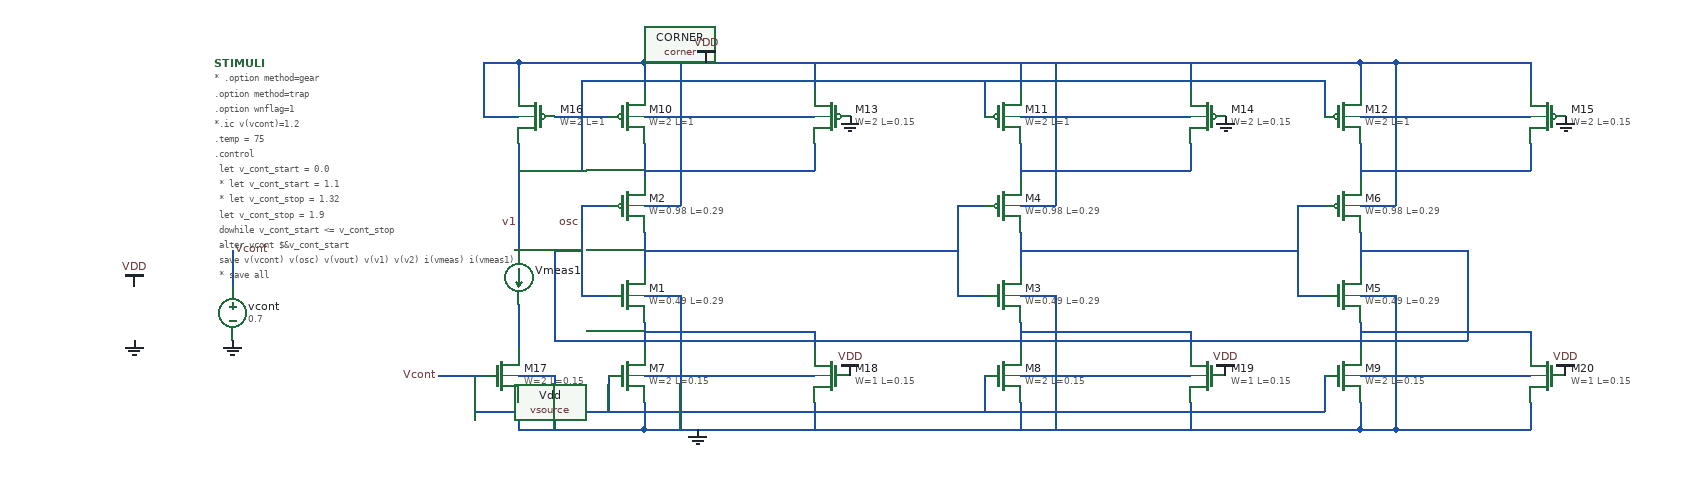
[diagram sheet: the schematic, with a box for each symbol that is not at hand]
v {xschem version=3.4.5 file_version=1.2
}
G {}
K {}
V {}
S {}
E {}
B 2 20 -1720 1940 -940 {flags=graph
y1=-0.052
y2=1.9
ypos1=0
ypos2=2
divy=5
subdivy=1
unity=1
x1=2.1401577e-08
x2=2.3050844e-08
divx=5
subdivx=4
xlabmag=1.0
ylabmag=1.0


dataset=-1
unitx=1
logx=0
logy=0
linewidth_mult=3




color=5
node=osc}
N 350 -670 350 -630 {
lab=Vcont}
N 810 -690 810 -650 {
lab=#net1}
N 740 -720 770 -720 {
lab=osc}
N 740 -720 740 -620 {
lab=osc}
N 740 -620 770 -620 {
lab=osc}
N 1230 -690 1230 -650 {
lab=#net2}
N 1160 -720 1190 -720 {
lab=#net1}
N 1160 -720 1160 -620 {
lab=#net1}
N 1160 -620 1190 -620 {
lab=#net1}
N 810 -670 1160 -670 {
lab=#net1}
N 1610 -690 1610 -650 {
lab=osc}
N 1540 -720 1570 -720 {
lab=#net2}
N 1540 -720 1540 -620 {
lab=#net2}
N 1540 -620 1570 -620 {
lab=#net2}
N 1230 -670 1540 -670 {
lab=#net2}
N 810 -500 810 -470 {
lab=GND}
N 810 -470 1610 -470 {
lab=GND}
N 1610 -500 1610 -470 {
lab=GND}
N 1230 -500 1230 -470 {
lab=GND}
N 1610 -670 1730 -670 {
lab=osc}
N 1730 -670 1730 -570 {
lab=osc}
N 710 -570 1730 -570 {
lab=osc}
N 710 -670 710 -570 {
lab=osc}
N 710 -670 740 -670 {
lab=osc}
N 810 -790 810 -750 {
lab=#net3}
N 810 -790 810 -750 {
lab=#net3}
N 1230 -790 1230 -750 {
lab=#net4}
N 1610 -790 1610 -750 {
lab=#net5}
N 810 -880 810 -850 {
lab=VDD}
N 810 -880 1610 -880 {
lab=VDD}
N 1610 -880 1610 -850 {
lab=VDD}
N 1230 -880 1230 -850 {
lab=VDD}
N 670 -880 670 -850 {
lab=VDD}
N 670 -880 810 -880 {
lab=VDD}
N 740 -820 740 -760 {
lab=v1}
N 670 -760 740 -760 {
lab=v1}
N 670 -500 670 -470 {
lab=GND}
N 670 -470 810 -470 {
lab=GND}
N 580 -530 630 -530 {
lab=Vcont}
N 1610 -590 1610 -560 {
lab=#net6}
N 1230 -590 1230 -560 {
lab=#net7}
N 810 -590 810 -560 {
lab=#net8}
N 810 -720 850 -720 {
lab=VDD}
N 850 -880 850 -720 {
lab=VDD}
N 850 -620 850 -470 {
lab=GND}
N 810 -530 850 -530 {
lab=GND}
N 1230 -620 1270 -620 {
lab=GND}
N 1270 -620 1270 -470 {
lab=GND}
N 1230 -530 1270 -530 {
lab=GND}
N 1610 -620 1650 -620 {
lab=GND}
N 1650 -620 1650 -470 {
lab=GND}
N 1610 -470 1650 -470 {
lab=GND}
N 1610 -530 1650 -530 {
lab=GND}
N 710 -820 770 -820 {
lab=v1}
N 810 -820 850 -820 {
lab=VDD}
N 1230 -820 1270 -820 {
lab=VDD}
N 1230 -720 1270 -720 {
lab=VDD}
N 1270 -880 1270 -720 {
lab=VDD}
N 1610 -820 1650 -820 {
lab=VDD}
N 1610 -880 1650 -880 {
lab=VDD}
N 1650 -880 1650 -720 {
lab=VDD}
N 1610 -720 1650 -720 {
lab=VDD}
N 740 -860 740 -820 {
lab=v1}
N 740 -860 1570 -860 {
lab=v1}
N 1570 -860 1570 -820 {
lab=v1}
N 1190 -860 1190 -820 {
lab=v1}
N 620 -530 620 -490 {
lab=Vcont}
N 620 -490 1570 -490 {
lab=Vcont}
N 1570 -530 1570 -490 {
lab=Vcont}
N 1190 -530 1190 -490 {
lab=Vcont}
N 770 -530 770 -490 {
lab=Vcont}
N 630 -820 670 -820 {
lab=VDD}
N 630 -880 630 -820 {
lab=VDD}
N 630 -880 670 -880 {
lab=VDD}
N 670 -530 710 -530 {
lab=GND}
N 710 -530 710 -470 {
lab=GND}
N 670 -610 670 -560 {
lab=#net9}
N 670 -790 670 -670 {
lab=v1}
N 1000 -880 1000 -850 {
lab=VDD}
N 850 -820 1000 -820 {
lab=VDD}
N 1000 -790 1000 -760 {
lab=#net3}
N 810 -760 1000 -760 {
lab=#net3}
N 1420 -880 1420 -850 {
lab=VDD}
N 1270 -820 1420 -820 {
lab=VDD}
N 1230 -760 1420 -760 {
lab=#net4}
N 1420 -790 1420 -760 {
lab=#net4}
N 1800 -880 1800 -850 {
lab=VDD}
N 1650 -820 1800 -820 {
lab=VDD}
N 1610 -760 1800 -760 {
lab=#net5}
N 1800 -790 1800 -760 {
lab=#net5}
N 1650 -880 1800 -880 {
lab=VDD}
N 810 -580 1000 -580 {
lab=#net8}
N 1000 -580 1000 -550 {
lab=#net8}
N 850 -530 1000 -530 {
lab=GND}
N 1000 -500 1000 -470 {
lab=GND}
N 1230 -580 1420 -580 {
lab=#net7}
N 1420 -580 1420 -550 {
lab=#net7}
N 1270 -530 1420 -530 {
lab=GND}
N 1420 -500 1420 -470 {
lab=GND}
N 1610 -580 1800 -580 {
lab=#net6}
N 1800 -580 1800 -550 {
lab=#net6}
N 1650 -530 1800 -530 {
lab=GND}
N 1800 -500 1800 -470 {
lab=GND}
N 1650 -470 1800 -470 {
lab=GND}
N 810 -620 850 -620 {
lab=GND}
C {devices/vsource.sym} 240 -600 0 0 {name=Vdd value=1.8 savecurrent=false
* "pwl()"}
C {devices/gnd.sym} 240 -570 0 0 {name=l3 lab=GND}
C {devices/vdd.sym} 240 -630 0 0 {name=l4 lab=VDD}
C {devices/vsource.sym} 350 -600 0 0 {name=vcont value=0.7 savecurrent=false}
C {devices/gnd.sym} 350 -570 0 0 {name=l5 lab=GND}
C {devices/lab_pin.sym} 350 -670 0 1 {name=p1 sig_type=std_logic lab=Vcont}
C {sky130_fd_pr/corner.sym} 180 -880 0 0 {name=CORNER only_toplevel=false corner=tt}
C {devices/code.sym} 330 -878.75 0 0 {name=STIMULI only_toplevel=false value="

* .option method=gear
.option method=trap
.option wnflag=1


*.ic v(vcont)=1.2

.temp = 75

.control

  let v_cont_start = 0.0
  * let v_cont_start = 1.1
  * let v_cont_stop = 1.32
  let v_cont_stop = 1.9  

  dowhile v_cont_start <= v_cont_stop
    alter vcont $&v_cont_start
    save v(vcont) v(osc) v(vout) v(v1) v(v2) i(vmeas) i(vmeas1)
    * save all
    tran 1ps 30ns
    remzerovec
    write tb_current_starved_VCO4_4_\{$&v_cont_start\}.raw
    * write tb_current_starved_VCO4_4_.raw
    linearize v(osc)
    let filename = v_cont_start * 100
    wrdata /foss/designs/my_design/projects/pll/vco/xschem_ngspice/tb_current_starved_VCO4_4_\{$&filename\}.txt v(osc)
    set appendwrite

    reset
    let v_cont_start = v_cont_start + 0.1
  end
.endc


"}
C {devices/vdd.sym} 880 -880 0 0 {name=l1 lab=VDD}
C {devices/gnd.sym} 870 -470 0 0 {name=l2 lab=GND}
C {sky130_fd_pr/nfet_01v8.sym} 790 -620 0 0 {name=M1
L=0.29
W=0.49
nf=1 
mult=1
ad="'int((nf+1)/2) * W/nf * 0.29'" 
pd="'2*int((nf+1)/2) * (W/nf + 0.29)'"
as="'int((nf+2)/2) * W/nf * 0.29'" 
ps="'2*int((nf+2)/2) * (W/nf + 0.29)'"
nrd="'0.29 / W'" nrs="'0.29 / W'"
sa=0 sb=0 sd=0
model=nfet_01v8
spiceprefix=X
}
C {sky130_fd_pr/pfet_01v8.sym} 790 -720 0 0 {name=M2
L=0.29
W=0.98
nf=2
mult=1
ad="'int((nf+1)/2) * W/nf * 0.29'" 
pd="'2*int((nf+1)/2) * (W/nf + 0.29)'"
as="'int((nf+2)/2) * W/nf * 0.29'" 
ps="'2*int((nf+2)/2) * (W/nf + 0.29)'"
nrd="'0.29 / W'" nrs="'0.29 / W'"
sa=0 sb=0 sd=0
model=pfet_01v8
spiceprefix=X
}
C {sky130_fd_pr/nfet_01v8.sym} 1210 -620 0 0 {name=M3
L=0.29
W=0.49
nf=1 
mult=1
ad="'int((nf+1)/2) * W/nf * 0.29'" 
pd="'2*int((nf+1)/2) * (W/nf + 0.29)'"
as="'int((nf+2)/2) * W/nf * 0.29'" 
ps="'2*int((nf+2)/2) * (W/nf + 0.29)'"
nrd="'0.29 / W'" nrs="'0.29 / W'"
sa=0 sb=0 sd=0
model=nfet_01v8
spiceprefix=X
}
C {sky130_fd_pr/pfet_01v8.sym} 1210 -720 0 0 {name=M4
L=0.29
W=0.98
nf=2
mult=1
ad="'int((nf+1)/2) * W/nf * 0.29'" 
pd="'2*int((nf+1)/2) * (W/nf + 0.29)'"
as="'int((nf+2)/2) * W/nf * 0.29'" 
ps="'2*int((nf+2)/2) * (W/nf + 0.29)'"
nrd="'0.29 / W'" nrs="'0.29 / W'"
sa=0 sb=0 sd=0
model=pfet_01v8
spiceprefix=X
}
C {sky130_fd_pr/nfet_01v8.sym} 1590 -620 0 0 {name=M5
L=0.29
W=0.49
nf=1 
mult=1
ad="'int((nf+1)/2) * W/nf * 0.29'" 
pd="'2*int((nf+1)/2) * (W/nf + 0.29)'"
as="'int((nf+2)/2) * W/nf * 0.29'" 
ps="'2*int((nf+2)/2) * (W/nf + 0.29)'"
nrd="'0.29 / W'" nrs="'0.29 / W'"
sa=0 sb=0 sd=0
model=nfet_01v8
spiceprefix=X
}
C {sky130_fd_pr/pfet_01v8.sym} 1590 -720 0 0 {name=M6
L=0.29
W=0.98
nf=2
mult=1
ad="'int((nf+1)/2) * W/nf * 0.29'" 
pd="'2*int((nf+1)/2) * (W/nf + 0.29)'"
as="'int((nf+2)/2) * W/nf * 0.29'" 
ps="'2*int((nf+2)/2) * (W/nf + 0.29)'"
nrd="'0.29 / W'" nrs="'0.29 / W'"
sa=0 sb=0 sd=0
model=pfet_01v8
spiceprefix=X
}
C {sky130_fd_pr/nfet_01v8.sym} 790 -530 0 0 {name=M7
L=0.15
W=2
nf=1 
mult=1
ad="'int((nf+1)/2) * W/nf * 0.29'" 
pd="'2*int((nf+1)/2) * (W/nf + 0.29)'"
as="'int((nf+2)/2) * W/nf * 0.29'" 
ps="'2*int((nf+2)/2) * (W/nf + 0.29)'"
nrd="'0.29 / W'" nrs="'0.29 / W'"
sa=0 sb=0 sd=0
model=nfet_01v8
spiceprefix=X
}
C {sky130_fd_pr/nfet_01v8.sym} 1210 -530 0 0 {name=M8
L=0.15
W=2
nf=1 
mult=1
ad="'int((nf+1)/2) * W/nf * 0.29'" 
pd="'2*int((nf+1)/2) * (W/nf + 0.29)'"
as="'int((nf+2)/2) * W/nf * 0.29'" 
ps="'2*int((nf+2)/2) * (W/nf + 0.29)'"
nrd="'0.29 / W'" nrs="'0.29 / W'"
sa=0 sb=0 sd=0
model=nfet_01v8
spiceprefix=X
}
C {sky130_fd_pr/nfet_01v8.sym} 1590 -530 0 0 {name=M9
L=0.15
W=2
nf=1 
mult=1
ad="'int((nf+1)/2) * W/nf * 0.29'" 
pd="'2*int((nf+1)/2) * (W/nf + 0.29)'"
as="'int((nf+2)/2) * W/nf * 0.29'" 
ps="'2*int((nf+2)/2) * (W/nf + 0.29)'"
nrd="'0.29 / W'" nrs="'0.29 / W'"
sa=0 sb=0 sd=0
model=nfet_01v8
spiceprefix=X
}
C {sky130_fd_pr/pfet_01v8.sym} 790 -820 0 0 {name=M10
L=1
W=2
nf=1
mult=1
ad="'int((nf+1)/2) * W/nf * 0.29'" 
pd="'2*int((nf+1)/2) * (W/nf + 0.29)'"
as="'int((nf+2)/2) * W/nf * 0.29'" 
ps="'2*int((nf+2)/2) * (W/nf + 0.29)'"
nrd="'0.29 / W'" nrs="'0.29 / W'"
sa=0 sb=0 sd=0
model=pfet_01v8
spiceprefix=X
}
C {sky130_fd_pr/pfet_01v8.sym} 1210 -820 0 0 {name=M11
L=1
W=2
nf=1
mult=1
ad="'int((nf+1)/2) * W/nf * 0.29'" 
pd="'2*int((nf+1)/2) * (W/nf + 0.29)'"
as="'int((nf+2)/2) * W/nf * 0.29'" 
ps="'2*int((nf+2)/2) * (W/nf + 0.29)'"
nrd="'0.29 / W'" nrs="'0.29 / W'"
sa=0 sb=0 sd=0
model=pfet_01v8
spiceprefix=X
}
C {sky130_fd_pr/pfet_01v8.sym} 1590 -820 0 0 {name=M12
L=1
W=2
nf=1
mult=1
ad="'int((nf+1)/2) * W/nf * 0.29'" 
pd="'2*int((nf+1)/2) * (W/nf + 0.29)'"
as="'int((nf+2)/2) * W/nf * 0.29'" 
ps="'2*int((nf+2)/2) * (W/nf + 0.29)'"
nrd="'0.29 / W'" nrs="'0.29 / W'"
sa=0 sb=0 sd=0
model=pfet_01v8
spiceprefix=X
}
C {sky130_fd_pr/pfet_01v8.sym} 690 -820 0 1 {name=M16
L=1
W=2
nf=1
mult=1
ad="'int((nf+1)/2) * W/nf * 0.29'" 
pd="'2*int((nf+1)/2) * (W/nf + 0.29)'"
as="'int((nf+2)/2) * W/nf * 0.29'" 
ps="'2*int((nf+2)/2) * (W/nf + 0.29)'"
nrd="'0.29 / W'" nrs="'0.29 / W'"
sa=0 sb=0 sd=0
model=pfet_01v8
spiceprefix=X
}
C {sky130_fd_pr/nfet_01v8.sym} 650 -530 0 0 {name=M17
L=0.15
W=2
nf=1 
mult=1
ad="'int((nf+1)/2) * W/nf * 0.29'" 
pd="'2*int((nf+1)/2) * (W/nf + 0.29)'"
as="'int((nf+2)/2) * W/nf * 0.29'" 
ps="'2*int((nf+2)/2) * (W/nf + 0.29)'"
nrd="'0.29 / W'" nrs="'0.29 / W'"
sa=0 sb=0 sd=0
model=nfet_01v8
spiceprefix=X
}
C {devices/lab_pin.sym} 580 -530 0 0 {name=p2 sig_type=std_logic lab=Vcont}
C {devices/lab_pin.sym} 740 -700 0 0 {name=p3 sig_type=std_logic lab=osc}
C {devices/lab_pin.sym} 670 -700 0 0 {name=p4 sig_type=std_logic lab=v1}
C {devices/ammeter.sym} 670 -640 0 0 {name=Vmeas1 savecurrent=true spice_ignore=0}
C {sky130_fd_pr/pfet_01v8.sym} 1020 -820 0 1 {name=M13
L=0.15
W=2
nf=2
mult=1
ad="'int((nf+1)/2) * W/nf * 0.29'" 
pd="'2*int((nf+1)/2) * (W/nf + 0.29)'"
as="'int((nf+2)/2) * W/nf * 0.29'" 
ps="'2*int((nf+2)/2) * (W/nf + 0.29)'"
nrd="'0.29 / W'" nrs="'0.29 / W'"
sa=0 sb=0 sd=0
model=pfet_01v8
spiceprefix=X
}
C {devices/gnd.sym} 1040 -820 0 0 {name=l6 lab=GND}
C {sky130_fd_pr/pfet_01v8.sym} 1440 -820 0 1 {name=M14
L=0.15
W=2
nf=2
mult=1
ad="'int((nf+1)/2) * W/nf * 0.29'" 
pd="'2*int((nf+1)/2) * (W/nf + 0.29)'"
as="'int((nf+2)/2) * W/nf * 0.29'" 
ps="'2*int((nf+2)/2) * (W/nf + 0.29)'"
nrd="'0.29 / W'" nrs="'0.29 / W'"
sa=0 sb=0 sd=0
model=pfet_01v8
spiceprefix=X
}
C {devices/gnd.sym} 1460 -820 0 0 {name=l7 lab=GND}
C {sky130_fd_pr/pfet_01v8.sym} 1820 -820 0 1 {name=M15
L=0.15
W=2
nf=2
mult=1
ad="'int((nf+1)/2) * W/nf * 0.29'" 
pd="'2*int((nf+1)/2) * (W/nf + 0.29)'"
as="'int((nf+2)/2) * W/nf * 0.29'" 
ps="'2*int((nf+2)/2) * (W/nf + 0.29)'"
nrd="'0.29 / W'" nrs="'0.29 / W'"
sa=0 sb=0 sd=0
model=pfet_01v8
spiceprefix=X
}
C {devices/gnd.sym} 1840 -820 0 0 {name=l8 lab=GND}
C {sky130_fd_pr/nfet_01v8.sym} 1020 -530 0 1 {name=M18
L=0.15
W=1
nf=1 
mult=1
ad="'int((nf+1)/2) * W/nf * 0.29'" 
pd="'2*int((nf+1)/2) * (W/nf + 0.29)'"
as="'int((nf+2)/2) * W/nf * 0.29'" 
ps="'2*int((nf+2)/2) * (W/nf + 0.29)'"
nrd="'0.29 / W'" nrs="'0.29 / W'"
sa=0 sb=0 sd=0
model=nfet_01v8
spiceprefix=X
}
C {devices/vdd.sym} 1040 -530 0 0 {name=l9 lab=VDD}
C {sky130_fd_pr/nfet_01v8.sym} 1440 -530 0 1 {name=M19
L=0.15
W=1
nf=1 
mult=1
ad="'int((nf+1)/2) * W/nf * 0.29'" 
pd="'2*int((nf+1)/2) * (W/nf + 0.29)'"
as="'int((nf+2)/2) * W/nf * 0.29'" 
ps="'2*int((nf+2)/2) * (W/nf + 0.29)'"
nrd="'0.29 / W'" nrs="'0.29 / W'"
sa=0 sb=0 sd=0
model=nfet_01v8
spiceprefix=X
}
C {devices/vdd.sym} 1460 -530 0 0 {name=l10 lab=VDD}
C {sky130_fd_pr/nfet_01v8.sym} 1820 -530 0 1 {name=M20
L=0.15
W=1
nf=1 
mult=1
ad="'int((nf+1)/2) * W/nf * 0.29'" 
pd="'2*int((nf+1)/2) * (W/nf + 0.29)'"
as="'int((nf+2)/2) * W/nf * 0.29'" 
ps="'2*int((nf+2)/2) * (W/nf + 0.29)'"
nrd="'0.29 / W'" nrs="'0.29 / W'"
sa=0 sb=0 sd=0
model=nfet_01v8
spiceprefix=X
}
C {devices/vdd.sym} 1840 -530 0 0 {name=l11 lab=VDD}
